One B-rep face of a CAD part: STEP entity #686.
In plain terms, the planar face has unit normal (0, 0, 1).
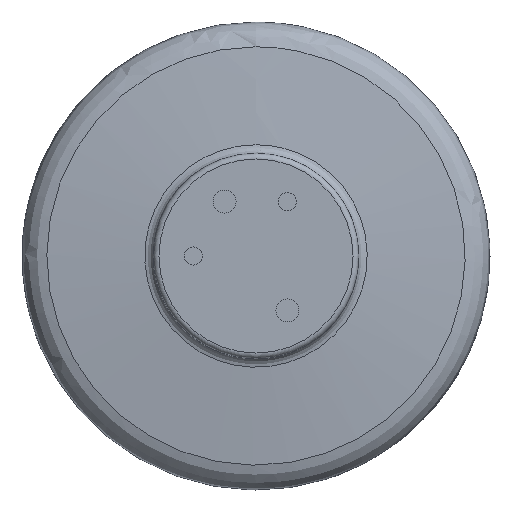
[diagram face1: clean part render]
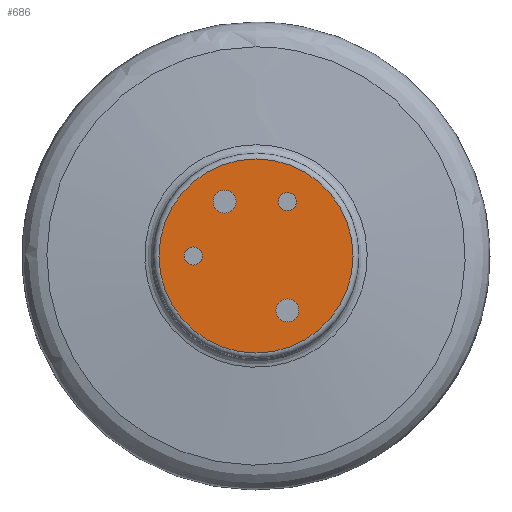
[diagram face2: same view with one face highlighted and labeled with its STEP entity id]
Its self-contained STEP definition (entity closure, numbers rounded to 3 decimals):
#512 = TOROIDAL_SURFACE('',#513,8.5,0.5);
#513 = AXIS2_PLACEMENT_3D('',#514,#515,#516);
#514 = CARTESIAN_POINT('',(0.,0.,11.3));
#515 = DIRECTION('',(0.,0.,1.));
#516 = DIRECTION('',(1.,0.,-0.));
#583 = VERTEX_POINT('',#584);
#584 = CARTESIAN_POINT('',(8.5,0.,11.8));
#606 = EDGE_CURVE('',#583,#583,#607,.T.);
#607 = SURFACE_CURVE('',#608,(#613,#620),.PCURVE_S1.);
#608 = CIRCLE('',#609,8.5);
#609 = AXIS2_PLACEMENT_3D('',#610,#611,#612);
#610 = CARTESIAN_POINT('',(0.,0.,11.8));
#611 = DIRECTION('',(0.,0.,1.));
#612 = DIRECTION('',(1.,0.,-0.));
#613 = PCURVE('',#512,#614);
#614 = DEFINITIONAL_REPRESENTATION('',(#615),#619);
#615 = LINE('',#616,#617);
#616 = CARTESIAN_POINT('',(0.,1.571));
#617 = VECTOR('',#618,1.);
#618 = DIRECTION('',(1.,0.));
#619 = ( GEOMETRIC_REPRESENTATION_CONTEXT(2) 
PARAMETRIC_REPRESENTATION_CONTEXT() REPRESENTATION_CONTEXT('2D SPACE',''
  ) );
#620 = PCURVE('',#621,#626);
#621 = PLANE('',#622);
#622 = AXIS2_PLACEMENT_3D('',#623,#624,#625);
#623 = CARTESIAN_POINT('',(0.,0.,11.8));
#624 = DIRECTION('',(0.,0.,1.));
#625 = DIRECTION('',(1.,0.,-0.));
#626 = DEFINITIONAL_REPRESENTATION('',(#627),#631);
#627 = CIRCLE('',#628,8.5);
#628 = AXIS2_PLACEMENT_2D('',#629,#630);
#629 = CARTESIAN_POINT('',(0.,0.));
#630 = DIRECTION('',(1.,0.));
#631 = ( GEOMETRIC_REPRESENTATION_CONTEXT(2) 
PARAMETRIC_REPRESENTATION_CONTEXT() REPRESENTATION_CONTEXT('2D SPACE',''
  ) );
#686 = ADVANCED_FACE('',(#687,#690,#721,#752,#783),#621,.T.);
#687 = FACE_BOUND('',#688,.T.);
#688 = EDGE_LOOP('',(#689));
#689 = ORIENTED_EDGE('',*,*,#606,.T.);
#690 = FACE_BOUND('',#691,.T.);
#691 = EDGE_LOOP('',(#692));
#692 = ORIENTED_EDGE('',*,*,#693,.F.);
#693 = EDGE_CURVE('',#694,#694,#696,.T.);
#694 = VERTEX_POINT('',#695);
#695 = CARTESIAN_POINT('',(-3.763,-2.75,11.8));
#696 = SURFACE_CURVE('',#697,(#702,#709),.PCURVE_S1.);
#697 = CIRCLE('',#698,1.);
#698 = AXIS2_PLACEMENT_3D('',#699,#700,#701);
#699 = CARTESIAN_POINT('',(-4.763,-2.75,11.8));
#700 = DIRECTION('',(0.,0.,1.));
#701 = DIRECTION('',(1.,0.,-0.));
#702 = PCURVE('',#621,#703);
#703 = DEFINITIONAL_REPRESENTATION('',(#704),#708);
#704 = CIRCLE('',#705,1.);
#705 = AXIS2_PLACEMENT_2D('',#706,#707);
#706 = CARTESIAN_POINT('',(-4.763,-2.75));
#707 = DIRECTION('',(1.,0.));
#708 = ( GEOMETRIC_REPRESENTATION_CONTEXT(2) 
PARAMETRIC_REPRESENTATION_CONTEXT() REPRESENTATION_CONTEXT('2D SPACE',''
  ) );
#709 = PCURVE('',#710,#715);
#710 = CYLINDRICAL_SURFACE('',#711,1.);
#711 = AXIS2_PLACEMENT_3D('',#712,#713,#714);
#712 = CARTESIAN_POINT('',(-4.763,-2.75,8.8));
#713 = DIRECTION('',(0.,0.,1.));
#714 = DIRECTION('',(1.,0.,-0.));
#715 = DEFINITIONAL_REPRESENTATION('',(#716),#720);
#716 = LINE('',#717,#718);
#717 = CARTESIAN_POINT('',(0.,3.));
#718 = VECTOR('',#719,1.);
#719 = DIRECTION('',(1.,0.));
#720 = ( GEOMETRIC_REPRESENTATION_CONTEXT(2) 
PARAMETRIC_REPRESENTATION_CONTEXT() REPRESENTATION_CONTEXT('2D SPACE',''
  ) );
#721 = FACE_BOUND('',#722,.T.);
#722 = EDGE_LOOP('',(#723));
#723 = ORIENTED_EDGE('',*,*,#724,.F.);
#724 = EDGE_CURVE('',#725,#725,#727,.T.);
#725 = VERTEX_POINT('',#726);
#726 = CARTESIAN_POINT('',(5.563,-2.75,11.8));
#727 = SURFACE_CURVE('',#728,(#733,#740),.PCURVE_S1.);
#728 = CIRCLE('',#729,0.8);
#729 = AXIS2_PLACEMENT_3D('',#730,#731,#732);
#730 = CARTESIAN_POINT('',(4.763,-2.75,11.8));
#731 = DIRECTION('',(0.,0.,1.));
#732 = DIRECTION('',(1.,0.,-0.));
#733 = PCURVE('',#621,#734);
#734 = DEFINITIONAL_REPRESENTATION('',(#735),#739);
#735 = CIRCLE('',#736,0.8);
#736 = AXIS2_PLACEMENT_2D('',#737,#738);
#737 = CARTESIAN_POINT('',(4.763,-2.75));
#738 = DIRECTION('',(1.,0.));
#739 = ( GEOMETRIC_REPRESENTATION_CONTEXT(2) 
PARAMETRIC_REPRESENTATION_CONTEXT() REPRESENTATION_CONTEXT('2D SPACE',''
  ) );
#740 = PCURVE('',#741,#746);
#741 = CYLINDRICAL_SURFACE('',#742,0.8);
#742 = AXIS2_PLACEMENT_3D('',#743,#744,#745);
#743 = CARTESIAN_POINT('',(4.763,-2.75,6.8));
#744 = DIRECTION('',(0.,0.,1.));
#745 = DIRECTION('',(1.,0.,-0.));
#746 = DEFINITIONAL_REPRESENTATION('',(#747),#751);
#747 = LINE('',#748,#749);
#748 = CARTESIAN_POINT('',(0.,5.));
#749 = VECTOR('',#750,1.);
#750 = DIRECTION('',(1.,0.));
#751 = ( GEOMETRIC_REPRESENTATION_CONTEXT(2) 
PARAMETRIC_REPRESENTATION_CONTEXT() REPRESENTATION_CONTEXT('2D SPACE',''
  ) );
#752 = FACE_BOUND('',#753,.T.);
#753 = EDGE_LOOP('',(#754));
#754 = ORIENTED_EDGE('',*,*,#755,.F.);
#755 = EDGE_CURVE('',#756,#756,#758,.T.);
#756 = VERTEX_POINT('',#757);
#757 = CARTESIAN_POINT('',(0.8,5.5,11.8));
#758 = SURFACE_CURVE('',#759,(#764,#771),.PCURVE_S1.);
#759 = CIRCLE('',#760,0.8);
#760 = AXIS2_PLACEMENT_3D('',#761,#762,#763);
#761 = CARTESIAN_POINT('',(0.,5.5,11.8));
#762 = DIRECTION('',(0.,0.,1.));
#763 = DIRECTION('',(1.,0.,-0.));
#764 = PCURVE('',#621,#765);
#765 = DEFINITIONAL_REPRESENTATION('',(#766),#770);
#766 = CIRCLE('',#767,0.8);
#767 = AXIS2_PLACEMENT_2D('',#768,#769);
#768 = CARTESIAN_POINT('',(0.,5.5));
#769 = DIRECTION('',(1.,0.));
#770 = ( GEOMETRIC_REPRESENTATION_CONTEXT(2) 
PARAMETRIC_REPRESENTATION_CONTEXT() REPRESENTATION_CONTEXT('2D SPACE',''
  ) );
#771 = PCURVE('',#772,#777);
#772 = CYLINDRICAL_SURFACE('',#773,0.8);
#773 = AXIS2_PLACEMENT_3D('',#774,#775,#776);
#774 = CARTESIAN_POINT('',(0.,5.5,6.8));
#775 = DIRECTION('',(0.,0.,1.));
#776 = DIRECTION('',(1.,0.,-0.));
#777 = DEFINITIONAL_REPRESENTATION('',(#778),#782);
#778 = LINE('',#779,#780);
#779 = CARTESIAN_POINT('',(0.,5.));
#780 = VECTOR('',#781,1.);
#781 = DIRECTION('',(1.,0.));
#782 = ( GEOMETRIC_REPRESENTATION_CONTEXT(2) 
PARAMETRIC_REPRESENTATION_CONTEXT() REPRESENTATION_CONTEXT('2D SPACE',''
  ) );
#783 = FACE_BOUND('',#784,.T.);
#784 = EDGE_LOOP('',(#785));
#785 = ORIENTED_EDGE('',*,*,#786,.F.);
#786 = EDGE_CURVE('',#787,#787,#789,.T.);
#787 = VERTEX_POINT('',#788);
#788 = CARTESIAN_POINT('',(5.763,2.75,11.8));
#789 = SURFACE_CURVE('',#790,(#795,#802),.PCURVE_S1.);
#790 = CIRCLE('',#791,1.);
#791 = AXIS2_PLACEMENT_3D('',#792,#793,#794);
#792 = CARTESIAN_POINT('',(4.763,2.75,11.8));
#793 = DIRECTION('',(0.,0.,1.));
#794 = DIRECTION('',(1.,0.,-0.));
#795 = PCURVE('',#621,#796);
#796 = DEFINITIONAL_REPRESENTATION('',(#797),#801);
#797 = CIRCLE('',#798,1.);
#798 = AXIS2_PLACEMENT_2D('',#799,#800);
#799 = CARTESIAN_POINT('',(4.763,2.75));
#800 = DIRECTION('',(1.,0.));
#801 = ( GEOMETRIC_REPRESENTATION_CONTEXT(2) 
PARAMETRIC_REPRESENTATION_CONTEXT() REPRESENTATION_CONTEXT('2D SPACE',''
  ) );
#802 = PCURVE('',#803,#808);
#803 = CYLINDRICAL_SURFACE('',#804,1.);
#804 = AXIS2_PLACEMENT_3D('',#805,#806,#807);
#805 = CARTESIAN_POINT('',(4.763,2.75,8.8));
#806 = DIRECTION('',(0.,0.,1.));
#807 = DIRECTION('',(1.,0.,-0.));
#808 = DEFINITIONAL_REPRESENTATION('',(#809),#813);
#809 = LINE('',#810,#811);
#810 = CARTESIAN_POINT('',(0.,3.));
#811 = VECTOR('',#812,1.);
#812 = DIRECTION('',(1.,0.));
#813 = ( GEOMETRIC_REPRESENTATION_CONTEXT(2) 
PARAMETRIC_REPRESENTATION_CONTEXT() REPRESENTATION_CONTEXT('2D SPACE',''
  ) );
